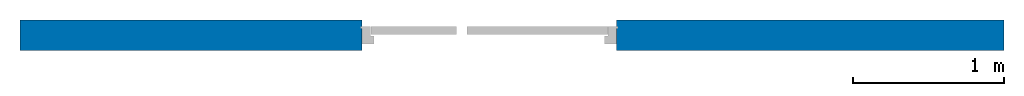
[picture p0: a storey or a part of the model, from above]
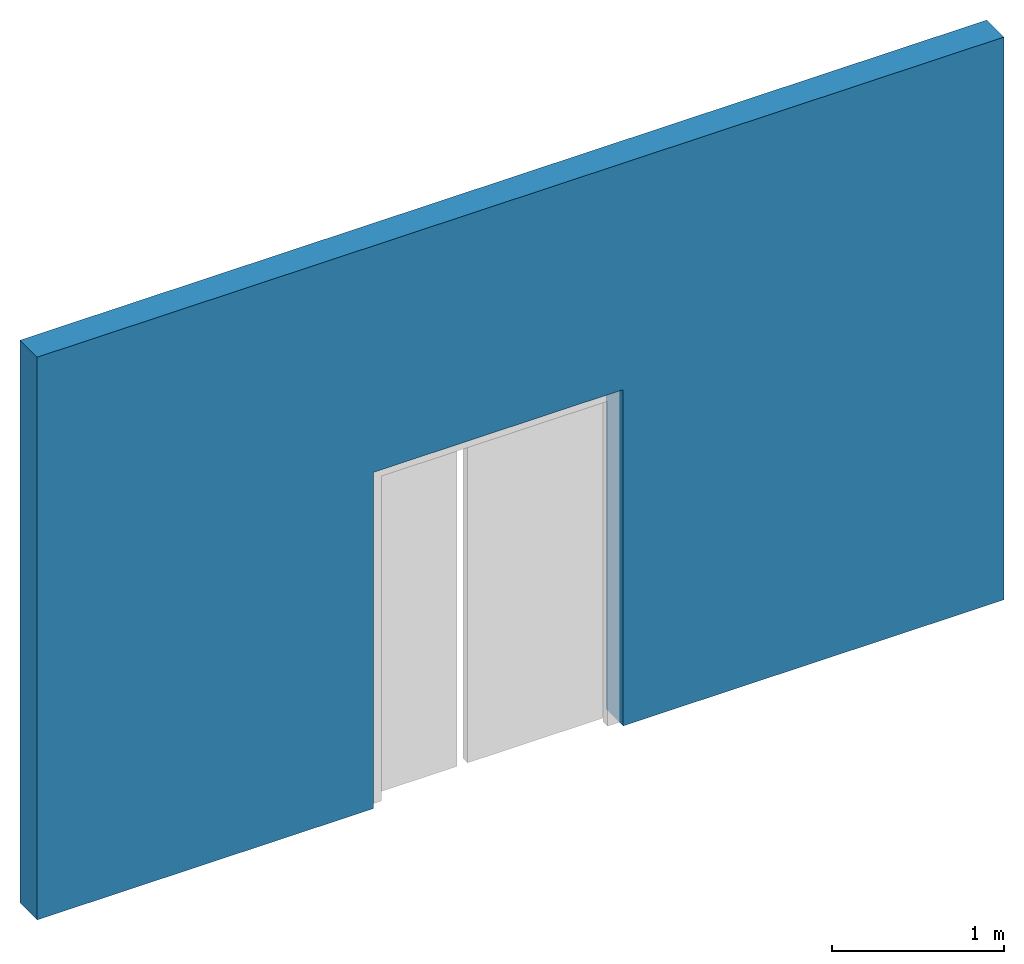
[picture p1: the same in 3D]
Properties of the parts of a building model (IFC2X3)

# File
Description: ViewDefinition [CoordinationView_V2.0, QuantityTakeOffAddOnView]
Time: 2021-02-24T07:49:57
Written by: The EXPRESS Data Manager Version 5.02.0100.07 : 28 Aug 2013
Made in: 20200826_1250(x64) - Exporter 20.3.1.0 - Alternate UI 20.3.1.0
Comment: STEP Physical File produced by: The EXPRESS Data Manager Version 5.02.0100.07 : 28 Aug 2013 * Module: EDMstepFileFactory/EDMstandAlone * Creation date: Wed Feb 24 07:49:57 2021 * Host: VASP10 * Database: C:\Users\G1E01~1.VAN\AppData\Local\Temp\4\4a1327d9-8008-4960-b6e6-1a8a2f1a80c7\97296708-5083-471e-9946-4fff27246ebb\ifc * Database version: 5507 * Database creation date: Wed Feb 24 07:49:52 2021 * Schema: IFC2X3 * Model: DataRepository.ifc * Model creation date: Wed Feb 24 07:49:52 2021 * Header model: DataRepository.ifc_HeaderModel * Header model creation date: Wed Feb 24 07:49:52 2021 * EDMuser: sdai-user * EDMgroup: sdai-group * License ID and type: 5605 : Permanent license. Expiry date: * EDMstepFileFactory options: 020000

# IfcSite, Default
RefLatitude: 42, 24, 53, 508911; RefLongitude: -71, -15, -29, -58837; RefElevation: 0 mm
Pset_ProductRequirements - Category: Project Information; sets with these values: 2

# IfcBuilding
Pset_BuildingCommon - NumberOfStoreys: 1
Pset_ProductRequirements - Category: Project Information; sets with these values: 2

# IfcBuildingStorey: Level:Level 1, Level 1
LongName: Level 1; Elevation: 0 mm
Pset_AirSideSystemInformation - Name: Level 1
Pset_ProductRequirements - Name: Level 1; Category: Levels
Constraints - Elevation: 0 mm
Dimensions - Computation Height: 0 mm
Identity Data - Structural: no; Building Story: yes; Name: Level 1
Other - Category: Levels; Family: Level: Level 1; Family and Type: Level: Level 1; Type: Level: Level 1; Type Id: Level: Level 1
Constraints(Type) - Elevation Base: Project Base Point
Graphics(Type) - Color: 0; Line Pattern: Solid; Line Weight: 1; Symbol at End 1 Default: no; Symbol at End 2 Default: yes
Identity Data(Type) - Type Name: Level 1
Other(Type) - Category: Levels; Family Name: Level

# IfcDoor: 32_binnendeur_kozijn_dubbel_2020:Merk_L, 32_binnendeur_kozijn_dubbel_2020:Merk_L:21217
In: Level 1
Type - ParameterTakesPrecedence: no; Sizeable: no; Classification: 32.31 (Uniformat); Material: <Unnamed>
Type - Analytical Properties - Analytic Construction: <None>; Define Thermal Properties by: Schematic Type
Type - Construction - Function: Interior; kozijn_breedte: 1700 mm; Wall Closure: By host
Type - Dimensions - bk_vrije_ruimte_deur: 3 mm; Breedte_deur: 930 mm; Deursponning_breedte: 25 mm; Deursponning_diepte: 62 mm; Dikte_deur: 54 mm; Draainaad: 25 mm; Draairichting_graden: 90 deg; Height: 0 mm; Hoogte_deur: 2312 mm; Kalksponning_breedte: 100 mm; Kalksponning_diepte: 10 mm; kozijn_hoogte: 2400 mm; Kozijnhout_breedte: 114 mm; Kozijnhout_dikte: 90 mm; offset_hart: 57 mm; ok_vrije_ruimte_deur: 20 mm; Rough Height: 0 mm; Rough Width: 0 mm; Sluitnaad: 25 mm; Thickness: 0 mm; Width: 0 mm
Type - Identity Data - Assembly Code: 32.31; Description: Merk HH-03; Fire Rating: 60; OmniClass Number: 23.30.10.00; OmniClass Title: Doors; Type Mark: 31; Type Name: Merk_L
Type - Other - Category: Doors; 30_min_brandwerend: no; 60_min_brandwerend: yes; Family Name: 32_binnendeur_kozijn_dubbel_2020; zelfsluitend: yes
Type - Pset_ConcreteElementGeneral - FireRating: 60
Type - Pset_DoorCommon - IsExternal: no; FireRating: 60
Type - Pset_ProductRequirements - Category: Doors
OverallHeight: 2390 mm; OverallWidth: 1680 mm
Pset_DoorCommon - Reference: Merk_L
Pset_QuantityTakeOff - Reference: Merk_L
BaseQuantities - Height: 0 mm; Width: 0 mm; Area: 0 m2
Constraints - Level: Level: Level 1; Sill Height: 0 mm
Dimensions - dagmaat_breedte: 1520 mm; dagmaat_hoogte: 2310 mm; restmaat_deur: 565 mm; Wand_in_kalksponning: 10 mm
Identity Data - Mark: 7
Other - Family: 32_binnendeur_kozijn_dubbel_2020: Merk_L; Family and Type: 32_binnendeur_kozijn_dubbel_2020: Merk_L; Head Height: 0 mm; Host Id: Basic Wall: Wall 1; Type: 32_binnendeur_kozijn_dubbel_2020: Merk_L; Type Id: 32_binnendeur_kozijn_dubbel_2020: Merk_L
Phasing - Phase Created: New Construction

# IfcDoor: 32_draairichting_deur:Type 1 (2)
In: Level 1
Type - ParameterTakesPrecedence: no; Sizeable: no; Classification: 32.30 (Uniformat); Material: n6_binnendeur
Type - Analytical Properties - Define Thermal Properties by: Schematic Type; Analytic Construction: <None>
Type - Dimensions - Dikte_deur: 40 mm
Type - Identity Data - Assembly Code: 32.30; Description: draairichting; Type Mark: 29; Type Name: Type 1
Type - Materials and Finishes - Material: n6_binnendeur
Type - Other - Category: Doors; Family Name: 32_draairichting_deur
Type - Pset_DoorCommon - IsExternal: no
Type - Pset_ProductRequirements - Category: Doors
OverallHeight: 2312 mm; Material: <Unnamed>
Pset_DoorCommon - Reference: Type 1
Pset_QuantityTakeOff - Reference: Type 1
BaseQuantities - Height: 2312 mm
Constraints - Level: Level: Level 1; Moves With Nearby Elements: no; Host: Basic Wall : Wall 1; Offset from Host: 20 mm
Dimensions - Angle: 90 deg; Height: 2312 mm; Percentage: 0; Rough Height: 2312 mm; Thickness: 54 mm
Other - Family: 32_draairichting_deur: Type 1; Family and Type: 32_draairichting_deur: Type 1; Type: 32_draairichting_deur: Type 1; Type Id: 32_draairichting_deur: Type 1
Phasing - Phase Created: New Construction
Name (32_draairichting_deur:Type 1:...) | OverallWidth (mm) = BaseQuantities, Width (mm) = Rough Width (mm) = Dimensions, Width (mm) | Area (m2) | Mark
21222 | 930 | 2.15016 | 9
21223 | 565 | 1.30628 | 8

# IfcDoor: 32_houten_deur:Binnendeur (2)
In: Level 1
Type - ParameterTakesPrecedence: no; Sizeable: no; Material: n6_binnendeur
Type - Analytical Properties - Define Thermal Properties by: Schematic Type; Analytic Construction: <None>
Type - Identity Data - Assembly Code: 31.31; Description: Binnen deur; Type Mark: 27; Type Name: Binnendeur
Type - Other - Category: Doors; Family Name: 32_houten_deur
Type - Pset_DoorCommon - IsExternal: no
Type - Pset_ProductRequirements - Category: Doors
OverallHeight: 2335 mm; Classification: 31.31 (Uniformat)
Pset_DoorCommon - Reference: Binnendeur
Pset_QuantityTakeOff - Reference: Binnendeur
Constraints - Level: Level: Level 1; Host: Basic Wall : Wall 1; Moves With Nearby Elements: no; Offset from Host: 0 mm
Dimensions - bk_vrije_ruimte_deur: 3 mm; Dikte_deur: 54 mm; Draainaad: 25 mm; Hoogte_deur: 2312 mm; ok_vrije_ruimte_deur: 20 mm; Sluitnaad: 25 mm
Other - Family: 32_houten_deur: Binnendeur; Family and Type: 32_houten_deur: Binnendeur; Type: 32_houten_deur: Binnendeur; Type Id: 32_houten_deur: Binnendeur
Phasing - Phase Created: New Construction
Name (32_houten_deur:Binnendeur:...) | OverallWidth (mm) | BaseQuantities, Area (m2) = Dimensions, Area (m2) | Breedte_deur (mm) | Volume (m3) | Mark
21219 | 615 | 1.46164 | 565 | 0.0705391 | 12
21221 | 980 | 2.32523 | 930 | 0.116109 | 10

# IfcDoor: 32_houten_kozijn_dubbel:Kozijn, 32_houten_kozijn_dubbel:Kozijn:21220
In: Level 1
Type - ParameterTakesPrecedence: no; Sizeable: no; Classification: 31.30 (Uniformat); Material: n6_binnenkozijn
Type - Analytical Properties - Define Thermal Properties by: Schematic Type; Analytic Construction: <None>
Type - Identity Data - Assembly Code: 31.30; Description: Binnendeur kozijn; Type Mark: 28; Type Name: Kozijn
Type - Other - Category: Doors; Family Name: 32_houten_kozijn_dubbel
Type - Pset_DoorCommon - IsExternal: no
Type - Pset_ProductRequirements - Category: Doors
OverallHeight: 2400 mm; OverallWidth: 1700 mm
Pset_DoorCommon - Reference: Kozijn
Pset_QuantityTakeOff - Reference: Kozijn
BaseQuantities - Area: 1.29809 m2
Constraints - Level: Level: Level 1; Moves With Nearby Elements: no; Offset from Host: 0 mm; Host: Basic Wall : Wall 1
Dimensions - Area: 1.29809 m2; Deursponning_breedte: 25 mm; Deursponning_diepte: 62 mm; Kalksponning_breedte: 100 mm; Kalksponning_diepte: 10 mm; Kozijn_breedte: 1700 mm; Kozijn_hoogte: 2400 mm; Kozijnhout_breedte: 114 mm; Kozijnhout_dikte: 90 mm; Volume: 0.0487687 m3
Identity Data - Mark: 11
Other - Family: 32_houten_kozijn_dubbel: Kozijn; Family and Type: 32_houten_kozijn_dubbel: Kozijn; Type: 32_houten_kozijn_dubbel: Kozijn; Type Id: 32_houten_kozijn_dubbel: Kozijn
Phasing - Phase Created: New Construction

# IfcOpeningElement: Opening, 32_binnendeur_kozijn_dubbel_2020:Merk_L:21217:1
In: Level 1
BaseQuantities - Depth: 200 mm; Height: 1680 mm; Width: 2390 mm

# IfcWallStandardCase: Basic Wall:Wall 1, Basic Wall:Wall 1:2513
In: Level 1
Type - PredefinedType: STANDARD; Material: Default Wall 200 mm
Type - Analytical Properties - Absorptance: 0.1; Roughness: 1
Type - Construction - Function: Exterior; Width: 200 mm; Wrapping at Inserts: Do not wrap
Type - Graphics - Coarse Scale Fill Color: 0
Type - Identity Data - Type Name: Wall 1
Type - Other - Category: Walls; Family Name: Basic Wall
Type - Pset_ElementShading - Roughness: 304.8 mm
Type - Pset_ProductRequirements - Category: Walls
Type - Pset_WallCommon - IsExternal: yes
BaseQuantities - Height: 4000 mm; Length: 6500 mm; Width: 200 mm; GrossFootprintArea: 1.3 m2; GrossVolume: 4396.96 m3; GrossSideArea: 21.9848 m2; NetSideArea: 21.9848 m2; NetVolume: 4.39696 m3
Constraints - Base Constraint: Level: Level 1; Base Extension Distance: 0 mm; Base is Attached: no; Base Offset: 0 mm; Location Line: Wall Centerline; Related to Mass: no; Room Bounding: yes; Top Extension Distance: 0 mm; Top is Attached: no; Top Offset: 0 mm; Unconnected Height: 4000 mm
Dimensions - Area: 21.9848 m2; Length: 6500 mm; Volume: 4.39696 m3
Other - Family: Basic Wall: Wall 1; Family and Type: Basic Wall: Wall 1; Type: Basic Wall: Wall 1; Type Id: Basic Wall: Wall 1
Phasing - Phase Created: New Construction
Structural - Enable Analytical Model: no; Structural: no; Structural Usage: Non-bearing
Pset_QuantityTakeOff - Reference: Wall 1; sets with these values: 2
Pset_WallCommon - Reference: Wall 1; ExtendToStructure: no; LoadBearing: no
